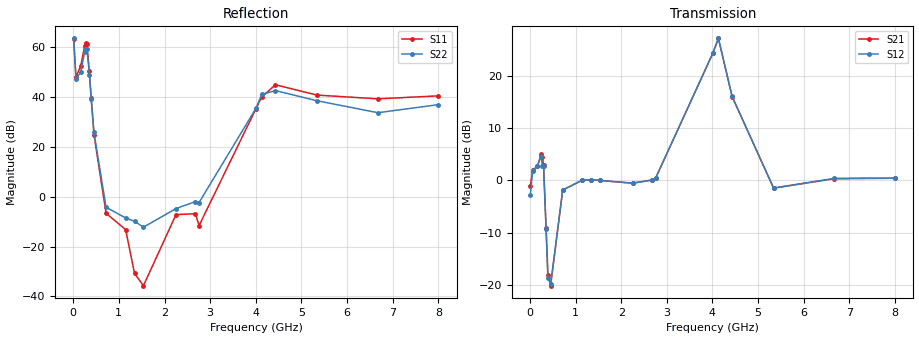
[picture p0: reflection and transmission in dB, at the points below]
!Agilent Technologies,N5230A,US43500312,A.07.50.67
!Agilent N5230A: A.07.50.67
!Date: Tuesday, June 09, 2015 15:38:55
!Correction: S11(Full 2 Port(1,2))
!S21(Full 2 Port(1,2))
!S12(Full 2 Port(1,2))
!S22(Full 2 Port(1,2))
!S2P File: Measurements: S11, S21, S12, S22:
# Hz S  MA  R 50
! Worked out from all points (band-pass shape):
!   1601 points, 10 MHz to 8 GHz, reference 50 ohm
!   highest |S21| = 27.08 dB at 4.13 GHz (marker M1); lowest = -20.1 dB at 454.4 MHz (marker M2)
!   |S21| within 3 dB of the highest: 4.003 GHz to 4.267 GHz (264.5 MHz wide, 6.4 % of centre)
!   lowest |S11| = -35.7 dB at 1.538 GHz (marker M3), VSWR 1.03, Z = 48.5 + j0.506 ohm
!   |S11| at or under -10 dB: 890.4 MHz to 2.165 GHz (1.275 GHz wide, 83.4 % of centre); 2.738 GHz to 2.917 GHz (178.5 MHz wide, 6.31 % of centre)
!   |S22| runs from -13.4 to 63.6 dB; largest |S21 - S12| = 0.41
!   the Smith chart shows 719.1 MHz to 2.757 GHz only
!   S11 on the Smith chart (normalised r, x): 719.1 MHz: 0.37, -0.16; 1.149 GHz: 1.43, +0.33; 2.252 GHz: 0.61, -0.67; 2.757 GHz: 0.84, -0.48
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1e7  1491 171.1  0.8866 -44.1  0.7234 -22.5  1519 -19.5
5.99375e7  253.4 328.9  1.251 -2.1  1.24 -4.0  228.2 93.0
1.648062e8  425.5 409.6  1.37 11.3  1.377 8.7  320.1 130.0
2.497e8  1064 404.5  1.774 3.1  1.722 -1.2  803.5 118.4
2.69675e8  1206 400.3  1.654 4.0  1.364 -1.4  924.2 114.6
2.996375e8  1190 424.2  1.405 32.5  1.361 45.2  939.8 141.2
3.545688e8  329.6 466.4  0.3538 86.1  0.3405 82.7  284.2 192.1
3.945188e8  95.69 468.4  0.1262 62.9  0.1172 56.7  90.04 204.8
4.544438e8  17.79 471.8  0.09893 59.6  0.1029 57.6  19.63 232.2
7.191125e8  0.4698 561.1  0.8106 130.9  0.8069 131.0  0.6179 435.9
1.148575e9  0.2196 750.0  1.005 100.4  1.004 100.5  0.3767 691.6
1.343331e9  0.02897 692.3  1.015 104.6  1.015 104.6  0.3238 762.8
1.538088e9  0.01647 521.5  0.9974 104.9  0.9986 105.0  0.2458 851.4
2.252194e9  0.441 262.4  0.9389 97.0  0.9424 97.0  0.5821 1130.7
2.676662e9  0.4584 262.3  1.007 109.8  1.01 109.8  0.8031 1220.8
2.756562e9  0.2648 266.6  1.055 110.3  1.057 110.3  0.768 1241.3
4.005e9  59.25 346.1  16.23 128.7  16.25 128.9  60.24 1529.8
4.129844e9  101.5 333.7  22.59 73.5  22.63 73.7  114.1 1505.9
4.429469e9  177.8 283.4  6.305 -43.9  6.33 -43.6  135.7 1441.9
5.338331e9  110.4 269.2  0.8434 17.2  0.8453 17.5  85.09 1412.2
6.671662e9  92.85 296.3  1.037 15.7  1.045 16.0  48.89 1353.0
8e9  106.5 316.8  1.048 10.3  1.052 11.1  70.97 1315.8
